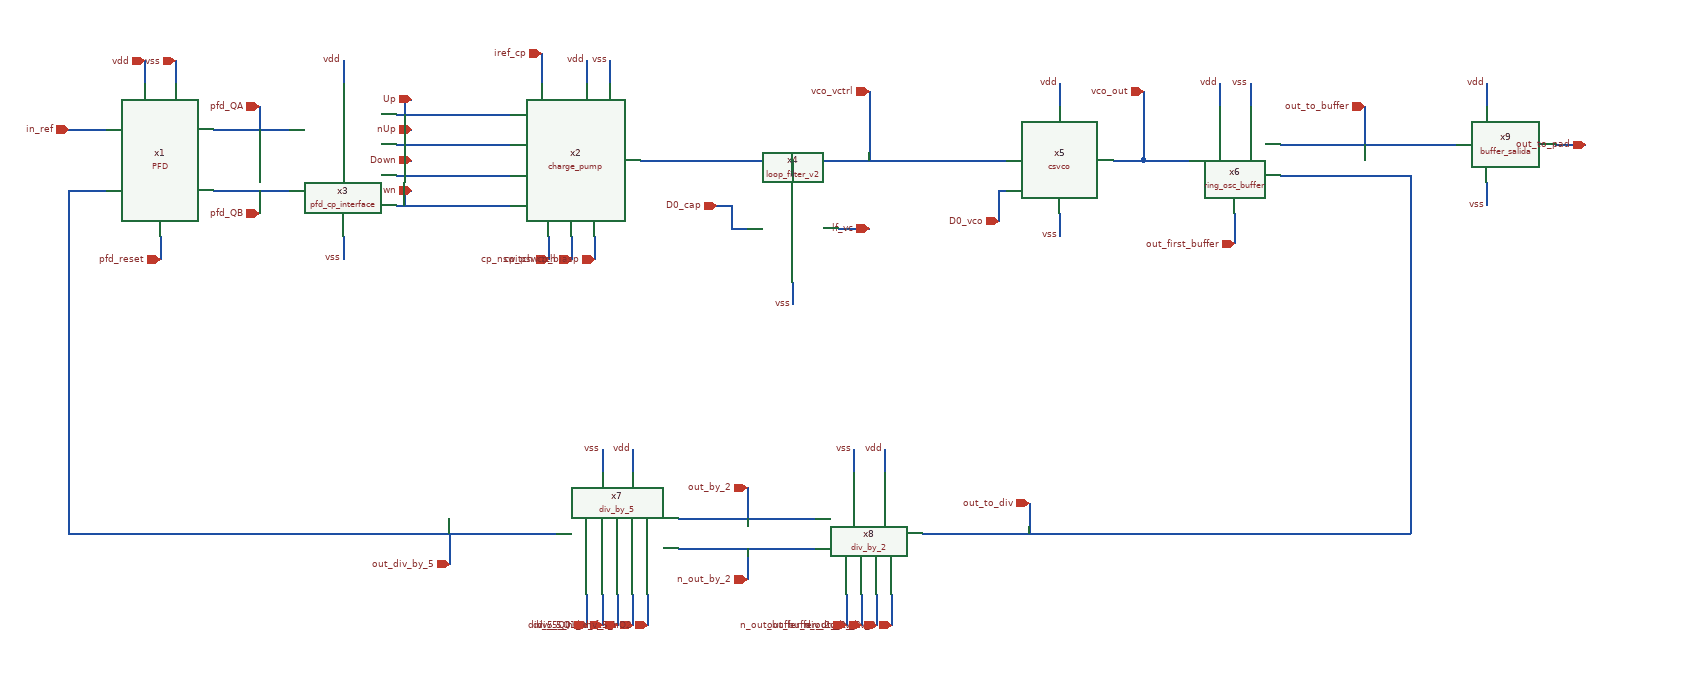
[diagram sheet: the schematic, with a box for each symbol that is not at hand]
v {xschem version=2.9.9 file_version=1.2 }
G {}
K {}
V {}
S {}
E {}
N -750 -360 -750 -330 { lab=vss}
N -890 -270 -850 -270 { lab=in_ref}
N -850 -270 -840 -270 { lab=in_ref}
N -890 -190 -840 -190 { lab=out_div_by_5}
N -790 -360 -790 -330 { lab=vdd}
N -400 -250 -310 -250 { lab=nUp}
N -400 -210 -310 -210 { lab=Down}
N -360 -170 -310 -170 { lab=nDown}
N -360 -290 -310 -290 { lab=Up}
N 410 -330 410 -300 { lab=vdd}
N 410 -160 410 -130 { lab=vss}
N 530 260 570 260 { lab=out_to_div}
N 330 -190 340 -190 { lab=vco_D0}
N 230 -230 340 -230 { lab=vco_vctrl}
N 480 -230 520 -230 { lab=vco_out}
N -460 -170 -360 -170 { lab=nDown}
N -460 -210 -400 -210 { lab=Down}
N -460 -250 -400 -250 { lab=nUp}
N -460 -290 -360 -290 { lab=Up}
N -700 -190 -600 -190 { lab=pfd_QB}
N -530 -360 -530 -330 { lab=vdd}
N -530 -130 -530 -100 { lab=vss}
N -890 -190 -890 260 { lab=out_div_by_5}
N 330 -190 330 -150 { lab=vco_D0}
N 180 150 180 180 { lab=vdd}
N -210 -360 -210 -330 { lab=vdd}
N -180 -360 -180 -330 { lab=vss}
N -50 -230 -30 -230 { lab=vco_vctrl}
N -270 -370 -270 -330 { lab=iref_cp}
N 10 280 90 280 { lab=n_out_by_2}
N 10 240 90 240 { lab=out_by_2}
N -60 240 10 240 { lab=out_by_2}
N -60 280 10 280 { lab=n_out_by_2}
N -190 150 -190 180 { lab=vss}
N -150 150 -150 180 { lab=vdd}
N -90 240 -60 240 { lab=out_by_2}
N -90 280 -60 280 { lab=n_out_by_2}
N -890 260 -470 260 { lab=out_div_by_5}
N 60 -70 60 -40 { lab=vss}
N 30 -230 90 -230 { lab=vco_vctrl}
N 90 -230 230 -230 { lab=vco_vctrl}
N 60 -230 60 -210 { lab=vco_vctrl}
N 120 -140 160 -140 { lab=lf_vc}
N 520 -230 580 -230 { lab=vco_out}
N 620 -330 620 -300 { lab=vdd}
N 660 -330 660 -300 { lab=vss}
N 700 -250 740 -250 { lab=out_to_buffer}
N 700 -210 750 -210 { lab=out_to_div}
N 870 -210 870 260 { lab=out_to_div}
N 570 260 750 260 { lab=out_to_div}
N 640 -160 640 -120 { lab=out_first_buffer}
N 750 -210 870 -210 { lab=out_to_div}
N 750 260 870 260 { lab=out_to_div}
N 230 260 530 260 { lab=out_to_div}
N -470 260 -250 260 { lab=out_div_by_5}
N 140 150 140 180 { lab=vss}
N -640 -300 -640 -270 { lab=pfd_QA}
N -640 -190 -640 -160 { lab=pfd_QB}
N -450 -310 -440 -310 { lab=Up}
N -450 -310 -450 -290 { lab=Up}
N -450 -270 -440 -270 { lab=nUp}
N -450 -270 -450 -250 { lab=nUp}
N -450 -230 -440 -230 { lab=Down}
N -450 -230 -450 -210 { lab=Down}
N -450 -190 -440 -190 { lab=nDown}
N -450 -190 -450 -170 { lab=nDown}
N -770 -130 -770 -100 { lab=pfd_reset}
N -700 -270 -600 -270 { lab=pfd_QA}
N -260 -130 -260 -100 { lab=cp_nswitch}
N -230 -130 -230 -100 { lab=cp_pswitch}
N -200 -130 -200 -100 { lab=cp_biasp}
N -140 -230 -50 -230 { lab=vco_vctrl}
N -30 -230 30 -230 { lab=vco_vctrl}
N 160 -320 160 -240 { lab=vco_vctrl}
N 160 -240 160 -230 { lab=vco_vctrl}
N 520 -320 520 -230 { lab=vco_out}
N 370 220 370 260 { lab=out_to_div}
N 0 200 0 240 { lab=out_by_2}
N 0 280 0 320 { lab=n_out_by_2}
N 190 340 190 380 { lab=out_div_2}
N 170 340 170 380 { lab=n_out_div_2}
N 150 340 150 380 { lab=out_buffer_div_2}
N 130 340 130 380 { lab=n_out_buffer_div_2}
N -150 340 -150 380 { lab=div_5_Q1}
N -170 340 -170 380 { lab=div_5_Q1_shift}
N -190 340 -190 380 { lab=div_5_nQ0}
N -210 340 -210 380 { lab=div_5_Q0}
N -130 340 -130 380 { lab=div_5_nQ2}
N -390 260 -390 300 { lab=out_div_by_5}
N 740 -250 930 -250 { lab=out_to_buffer}
N 810 -300 810 -250 { lab=out_to_buffer}
N 970 -330 970 -300 { lab=vdd}
N 970 -200 970 -170 { lab=vss}
N 1060 -250 1100 -250 { lab=out_to_pad}
N -40 -170 -20 -170 { lab=D0_cap}
N -20 -170 -20 -140 { lab=D0_cap}
N -20 -140 0 -140 { lab=D0_cap}
C {lab_pin.sym} 410 -330 1 0 {name=l38 sig_type=std_logic lab=vdd}
C {lab_pin.sym} 410 -130 3 0 {name=l39 sig_type=std_logic lab=vss}
C {lab_pin.sym} -530 -360 1 0 {name=l7 sig_type=std_logic lab=vdd}
C {lab_pin.sym} -530 -100 3 0 {name=l9 sig_type=std_logic lab=vss}
C {lab_pin.sym} 180 150 1 0 {name=l45 sig_type=std_logic lab=vdd}
C {lab_pin.sym} -210 -360 1 0 {name=l27 sig_type=std_logic lab=vdd}
C {lab_pin.sym} -180 -360 1 0 {name=l28 sig_type=std_logic lab=vss}
C {lab_pin.sym} -190 150 3 1 {name=l22 sig_type=std_logic lab=vss}
C {lab_pin.sym} -150 150 3 1 {name=l25 sig_type=std_logic lab=vdd}
C {lab_pin.sym} 60 -40 3 0 {name=l35 sig_type=std_logic lab=vss}
C {lab_pin.sym} 620 -330 1 0 {name=l16 sig_type=std_logic lab=vdd}
C {lab_pin.sym} 660 -330 1 0 {name=l40 sig_type=std_logic lab=vss}
C {lab_pin.sym} 140 150 1 0 {name=l12 sig_type=std_logic lab=vss}
C {iopin.sym} -790 -360 3 0 {name=p1 lab=vdd}
C {iopin.sym} -750 -360 3 0 {name=p2 lab=vss}
C {ipin.sym} -890 -270 0 0 {name=p3 lab=in_ref}
C {iopin.sym} -640 -300 3 0 {name=p4 lab=pfd_QA}
C {iopin.sym} -640 -160 1 0 {name=p5 lab=pfd_QB}
C {iopin.sym} -440 -310 0 0 {name=p6 lab=Up}
C {iopin.sym} -440 -270 0 0 {name=p7 lab=nUp}
C {iopin.sym} -440 -230 0 0 {name=p8 lab=Down}
C {iopin.sym} -440 -190 0 0 {name=p9 lab=nDown}
C {iopin.sym} -770 -100 1 0 {name=p10 lab=pfd_reset}
C {iopin.sym} -260 -100 1 0 {name=p11 lab=cp_nswitch}
C {iopin.sym} -230 -100 1 0 {name=p12 lab=cp_pswitch}
C {iopin.sym} -200 -100 1 0 {name=p13 lab=cp_biasp}
C {ipin.sym} -270 -370 1 0 {name=p14 lab=iref_cp}
C {iopin.sym} 160 -140 0 0 {name=p15 lab=lf_vc}
C {iopin.sym} 330 -150 1 0 {name=p16 lab=D0_vco}
C {iopin.sym} 160 -320 3 0 {name=p17 lab=vco_vctrl}
C {iopin.sym} 520 -320 3 0 {name=p18 lab=vco_out}
C {iopin.sym} 640 -120 1 0 {name=p19 lab=out_first_buffer}
C {iopin.sym} 810 -300 3 0 {name=p20 lab=out_to_buffer}
C {iopin.sym} 370 220 3 0 {name=p21 lab=out_to_div}
C {iopin.sym} 0 200 3 0 {name=p22 lab=out_by_2}
C {iopin.sym} 0 320 1 0 {name=p23 lab=n_out_by_2}
C {iopin.sym} 190 380 1 0 {name=p24 lab=out_div_2}
C {iopin.sym} 170 380 1 0 {name=p25 lab=n_out_div_2}
C {iopin.sym} 150 380 1 0 {name=p26 lab=out_buffer_div_2}
C {iopin.sym} 130 380 1 0 {name=p27 lab=n_out_buffer_div_2}
C {iopin.sym} -150 380 1 0 {name=p28 lab=div_5_Q1}
C {iopin.sym} -170 380 1 0 {name=p29 lab=div_5_Q1_shift}
C {iopin.sym} -190 380 1 0 {name=p30 lab=div_5_nQ0}
C {iopin.sym} -210 380 1 0 {name=p31 lab=div_5_Q0}
C {iopin.sym} -130 380 1 0 {name=p32 lab=div_5_nQ2}
C {iopin.sym} -390 300 1 0 {name=p33 lab=out_div_by_5}
C {PFD.sym} -770 -230 0 0 {name=x1}
C {charge_pump.sym} -230 -230 0 0 {name=x2}
C {pfd_cp_interface.sym} -530 -230 0 0 {name=x3}
C {csvco.sym} 410 -230 0 0 {name=x5}
C {ring_osc_buffer.sym} 640 -230 0 0 {name=x6}
C {div_by_5.sym} -170 260 0 1 {name=x7}
C {div_by_2.sym} 160 260 0 1 {name=x8}
C {buffer_salida.sym} 990 -250 0 0 {name=x9}
C {lab_pin.sym} 970 -330 1 0 {name=l1 sig_type=std_logic lab=vdd}
C {lab_pin.sym} 970 -170 3 0 {name=l2 sig_type=std_logic lab=vss}
C {iopin.sym} 1100 -250 0 0 {name=p35 lab=out_to_pad}
C {loop_filter_v2.sym} 60 -140 0 0 {name=x4}
C {ipin.sym} -40 -170 0 0 {name=p34 lab=D0_cap}
